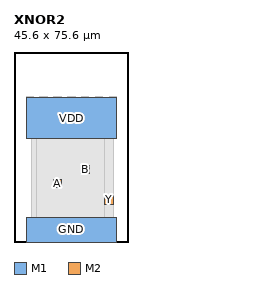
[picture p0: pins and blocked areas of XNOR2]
MACRO XNOR2
  CLASS CORE ;
  ORIGIN 0 0 ;
  SIZE 45.600 BY 75.600 ;
  SYMMETRY X Y ;
  SITE TR1um_access_site ;
  PIN VDD
    DIRECTION INOUT ;
    USE POWER ;
    PORT
      LAYER M1 ;
        RECT 5.000 41.000 40.600 57.600 ;
    END
  END VDD
  PIN GND
    DIRECTION INOUT ;
    USE GROUND ;
    PORT
      LAYER M1 ;
        RECT 5.000 0.000 40.600 9.800 ;
    END
  END GND
  PIN A
    DIRECTION INPUT ;
    USE SIGNAL ;
    PORT
      LAYER M2 ;
        RECT 15.600 21.600 19.000 25.000 ;
    END
  END A
  PIN B
    DIRECTION INPUT ;
    USE SIGNAL ;
    PORT
      LAYER M2 ;
        RECT 26.600 27.100 30.000 30.500 ;
    END
  END B
  PIN Y
    DIRECTION OUTPUT ;
    USE SIGNAL ;
    PORT
      LAYER M2 ;
        RECT 36.200 15.100 39.600 18.500 ;
    END
  END Y
  OBS
    LAYER M1 ;
      RECT 13.100 6.400 15.700 9.800 ;
    LAYER M1 ;
      RECT 25.100 6.400 35.700 13.600 ;
    LAYER M1 ;
      RECT 10.300 19.000 32.900 25.000 ;
    LAYER M1 ;
      RECT 15.900 23.800 30.000 30.500 ;
    LAYER M1 ;
      RECT 7.000 6.400 19.700 51.200 ;
    LAYER M1 ;
      RECT 29.100 41.000 31.700 51.200 ;
    LAYER M1 ;
      RECT 21.100 6.400 39.600 51.200 ;
    LAYER V1 ;
      RECT 4.800 0.000 7.800 2.800 ;
    LAYER V1 ;
      RECT 10.300 0.000 13.300 2.800 ;
    LAYER V1 ;
      RECT 15.800 0.000 18.800 2.800 ;
    LAYER V1 ;
      RECT 21.300 0.000 24.300 2.800 ;
    LAYER V1 ;
      RECT 26.800 0.000 29.800 2.800 ;
    LAYER V1 ;
      RECT 32.300 0.000 35.300 2.800 ;
    LAYER V1 ;
      RECT 37.800 0.000 40.800 2.800 ;
    LAYER V1 ;
      RECT 37.200 16.100 38.600 17.500 ;
    LAYER V1 ;
      RECT 16.600 22.600 18.000 24.000 ;
    LAYER V1 ;
      RECT 27.600 28.100 29.000 29.500 ;
    LAYER V1 ;
      RECT 8.900 4.000 35.900 53.600 ;
    LAYER V1 ;
      RECT 4.800 54.800 7.800 57.800 ;
    LAYER V1 ;
      RECT 10.300 54.800 13.300 57.800 ;
    LAYER V1 ;
      RECT 15.800 54.800 18.800 57.800 ;
    LAYER V1 ;
      RECT 21.300 54.800 24.300 57.800 ;
    LAYER V1 ;
      RECT 26.800 54.800 29.800 57.800 ;
    LAYER V1 ;
      RECT 32.300 54.800 35.300 57.800 ;
    LAYER V1 ;
      RECT 37.800 54.800 40.800 57.800 ;
  END
END XNOR2
